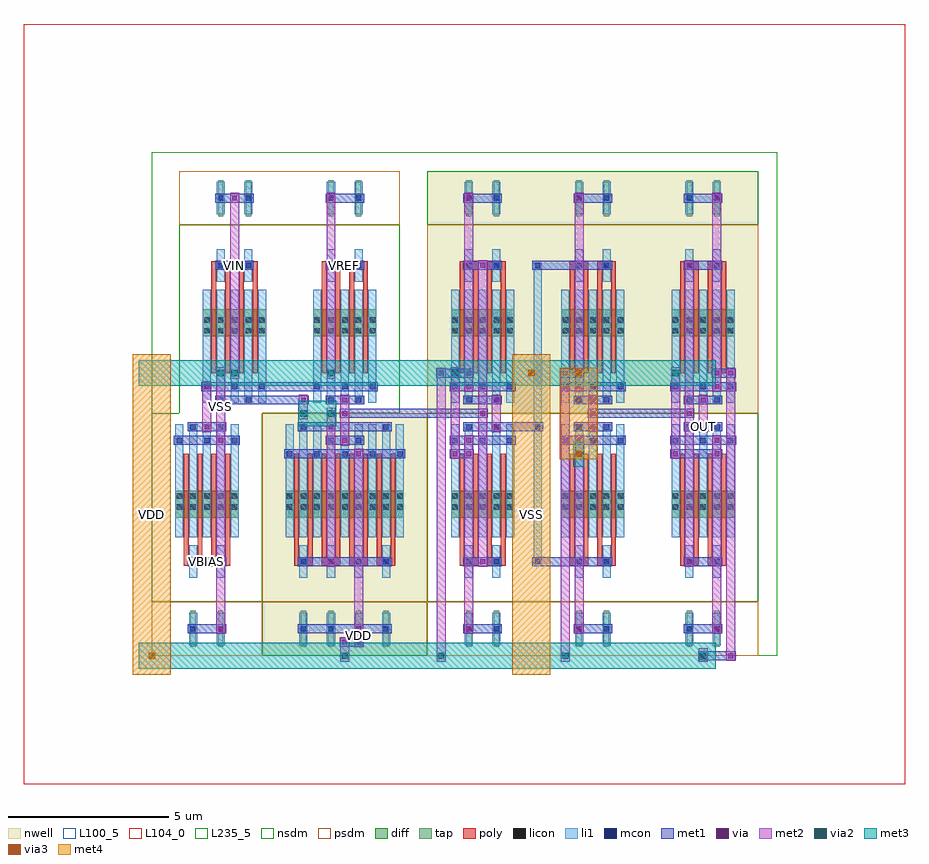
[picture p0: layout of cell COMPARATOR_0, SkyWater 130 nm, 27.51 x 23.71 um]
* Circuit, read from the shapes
.subckt COMPARATOR_0 OUT VBIAS VDD VIN VREF VSS
XM1 n1 VBIAS VSS VSS sky130_fd_pr__nfet_01v8 w=0.84 l=0.15 m=4
XM2 n2 VIN n1 VSS sky130_fd_pr__nfet_01v8 w=0.84 l=0.15 m=4
XM3 n3 VREF n1 VSS sky130_fd_pr__nfet_01v8 w=0.84 l=0.15 m=4
XM4 n4 n3 VSS VSS sky130_fd_pr__nfet_01v8 w=0.84 l=0.15 m=4
XM5 n5 n4 VSS VSS sky130_fd_pr__nfet_01v8 w=0.84 l=0.15 m=4
XM6 OUT n5 VSS VSS sky130_fd_pr__nfet_01v8 w=0.84 l=0.15 m=4
XM7 n2 n2 VDD VDD sky130_fd_pr__pfet_01v8 w=0.84 l=0.15 m=4
XM8 n3 n2 VDD VDD sky130_fd_pr__pfet_01v8 w=0.84 l=0.15 m=4
XM9 n4 n3 VDD VDD sky130_fd_pr__pfet_01v8 w=0.84 l=0.15 m=4
XM10 n5 n4 VDD VDD sky130_fd_pr__pfet_01v8 w=0.84 l=0.15 m=4
XM11 OUT n5 VDD VDD sky130_fd_pr__pfet_01v8 w=0.84 l=0.15 m=4
.ends

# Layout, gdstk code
from math import pi, radians
import gdstk
lib = gdstk.Library(unit=1e-6, precision=1e-09)
def R(c, l, rs):  # rectangles x0, y0, x1, y1
    for r in rs: c.add(gdstk.rectangle(r[:2], r[2:], *l))
def A(c, l, x, y, w, h, nx, ny, dx, dy):  # array of equal rectangles
    R(c, l, [(x+i*dx, y+j*dy, x+i*dx+w, y+j*dy+h) for i in range(nx) for j in range(ny)])
def P(c, l, *ps):  # polygons
    for p in ps: c.add(gdstk.Polygon(p, *l))
nwell = (64, 20)
diff = (65, 20)
tap = (65, 44)
poly = (66, 20)
licon = (66, 44)
li1 = (67, 20)
mcon = (67, 44)
met1 = (68, 20)
via = (68, 44)
met2 = (69, 20)
via2 = (69, 44)
met3 = (70, 20)
via3 = (70, 44)
met4 = (71, 20)
nsdm = (93, 44)
psdm = (94, 20)
L100_5 = (100, 5)
L104_0 = (104, 0)
L235_5 = (235, 5)

nmos_s_74334133_x2_y1_16 = lib.new_cell('NMOS_S_74334133_X2_Y1_1679758480_1679758482')
R(nmos_s_74334133_x2_y1_16, diff, [(0.735,2.415,2.705,3.255)])
R(nmos_s_74334133_x2_y1_16, tap, [(1.205,6.16,1.375,7.28), (2.065,6.16,2.235,7.28)])
A(nmos_s_74334133_x2_y1_16, poly, 1, 1.26, 0.15, 3.36, 4, 1, 0.43, 0)
R(nmos_s_74334133_x2_y1_16, poly, [(1,4.485,1.58,4.755), (1.86,4.485,2.44,4.755)])
A(nmos_s_74334133_x2_y1_16, licon, 0.775, 2.495, 0.17, 0.17, 3, 2, 0.43, 0.34)
A(nmos_s_74334133_x2_y1_16, licon, 1.635, 2.495, 0.17, 0.17, 3, 2, 0.43, 0.34)
R(nmos_s_74334133_x2_y1_16, licon, [(1.205,4.535,1.375,4.705), (2.065,4.535,2.235,4.705), (1.205,6.635,1.375,6.805), (2.065,6.635,2.235,6.805)])
A(nmos_s_74334133_x2_y1_16, li1, 0.735, 0.335, 0.25, 3.53, 5, 1, 0.43, 0)
R(nmos_s_74334133_x2_y1_16, li1, [(1.165,4.115,1.415,5.125), (2.025,4.115,2.275,5.125), (1.165,6.215,1.415,7.225), (2.025,6.215,2.275,7.225)])
A(nmos_s_74334133_x2_y1_16, mcon, 0.775, 0.755, 0.17, 0.17, 3, 1, 0.86, 0)
R(nmos_s_74334133_x2_y1_16, mcon, [(1.205,0.335,1.375,0.505), (2.065,0.335,2.235,0.505), (1.205,4.535,1.375,4.705), (2.065,4.535,2.235,4.705), (1.205,6.635,1.375,6.805), (2.065,6.635,2.235,6.805)])
R(nmos_s_74334133_x2_y1_16, met1, [(1.12,0.28,2.32,0.56), (0.69,0.7,2.75,0.98), (1.12,4.48,2.32,4.76), (1.12,6.58,2.32,6.86)])
R(nmos_s_74334133_x2_y1_16, via, [(2.075,0.765,2.225,0.915), (2.075,6.645,2.225,6.795)])
R(nmos_s_74334133_x2_y1_16, met2, [(2.01,0.68,2.29,6.88)])
R(nmos_s_74334133_x2_y1_16, nsdm, [(0,0,3.44,5.88)])
R(nmos_s_74334133_x2_y1_16, psdm, [(0,5.88,3.44,7.56)])
R(nmos_s_74334133_x2_y1_16, L100_5, [(0,0,3.44,7.56)])

pmos_s_33331942_x2_y1_16 = lib.new_cell('PMOS_S_33331942_X2_Y1_1679758481_1679758482')
R(pmos_s_33331942_x2_y1_16, nwell, [(0,0,3.44,7.56)])
R(pmos_s_33331942_x2_y1_16, diff, [(0.735,2.415,2.705,3.255)])
R(pmos_s_33331942_x2_y1_16, tap, [(1.205,6.16,1.375,7.28), (2.065,6.16,2.235,7.28)])
A(pmos_s_33331942_x2_y1_16, poly, 1, 1.26, 0.15, 3.36, 4, 1, 0.43, 0)
R(pmos_s_33331942_x2_y1_16, poly, [(1,4.485,1.58,4.755), (1.86,4.485,2.44,4.755)])
A(pmos_s_33331942_x2_y1_16, licon, 0.775, 2.495, 0.17, 0.17, 3, 2, 0.43, 0.34)
A(pmos_s_33331942_x2_y1_16, licon, 1.635, 2.495, 0.17, 0.17, 3, 2, 0.43, 0.34)
R(pmos_s_33331942_x2_y1_16, licon, [(1.205,4.535,1.375,4.705), (2.065,4.535,2.235,4.705), (1.205,6.635,1.375,6.805), (2.065,6.635,2.235,6.805)])
A(pmos_s_33331942_x2_y1_16, li1, 0.735, 0.335, 0.25, 3.53, 5, 1, 0.43, 0)
R(pmos_s_33331942_x2_y1_16, li1, [(1.165,4.115,1.415,5.125), (2.025,4.115,2.275,5.125), (1.165,6.215,1.415,7.225), (2.025,6.215,2.275,7.225)])
A(pmos_s_33331942_x2_y1_16, mcon, 0.775, 0.755, 0.17, 0.17, 3, 1, 0.86, 0)
R(pmos_s_33331942_x2_y1_16, mcon, [(1.205,0.335,1.375,0.505), (2.065,0.335,2.235,0.505), (1.205,4.535,1.375,4.705), (2.065,4.535,2.235,4.705), (1.205,6.635,1.375,6.805), (2.065,6.635,2.235,6.805)])
R(pmos_s_33331942_x2_y1_16, met1, [(1.12,0.28,2.32,0.56), (0.69,0.7,2.75,0.98), (1.12,4.48,2.32,4.76), (1.12,6.58,2.32,6.86)])
R(pmos_s_33331942_x2_y1_16, via, [(2.075,0.765,2.225,0.915), (2.075,6.645,2.225,6.795)])
R(pmos_s_33331942_x2_y1_16, met2, [(2.01,0.68,2.29,6.88)])
R(pmos_s_33331942_x2_y1_16, nsdm, [(0,5.88,3.44,7.56)])
R(pmos_s_33331942_x2_y1_16, psdm, [(0,0,3.44,5.88)])
R(pmos_s_33331942_x2_y1_16, L100_5, [(0,0,3.44,7.56)])

stage2_inv_90501218_pg0_ = lib.new_cell('STAGE2_INV_90501218_PG0_0_0_1679758482')
R(stage2_inv_90501218_pg0_, li1, [(3.315,2.855,3.565,3.025), (3.315,2.855,3.565,3.025), (3.315,2.855,3.565,3.025), (3.315,2.855,3.565,3.025), (3.315,2.855,3.565,3.025), (3.315,2.855,3.565,3.025), (3.315,2.94,3.565,7.14), (3.315,7.055,3.565,7.225), (3.315,7.055,3.565,7.225), (3.315,7.055,3.565,7.225), (3.315,7.055,3.565,7.225), (3.315,7.055,3.565,7.225), (3.315,7.055,3.565,7.225), (3.315,7.14,3.565,12.18), (3.315,12.095,3.565,12.265), (3.315,12.095,3.565,12.265)])
R(stage2_inv_90501218_pg0_, mcon, [(3.355,2.855,3.525,3.025), (3.355,2.855,3.525,3.025), (3.355,2.855,3.525,3.025), (3.355,2.855,3.525,3.025), (3.355,2.855,3.525,3.025), (3.355,2.855,3.525,3.025), (3.355,7.055,3.525,7.225), (3.355,7.055,3.525,7.225), (3.355,7.055,3.525,7.225), (3.355,7.055,3.525,7.225), (3.355,7.055,3.525,7.225), (3.355,7.055,3.525,7.225), (3.355,12.095,3.525,12.265), (3.355,12.095,3.525,12.265)])
R(stage2_inv_90501218_pg0_, met1, [(2.15,2.8,3.44,3.08), (3.27,2.8,3.61,3.08), (3.27,2.8,3.61,3.08), (3.27,2.8,3.61,3.08), (3.27,2.8,3.61,3.08), (3.27,2.8,3.61,3.08), (3.27,2.8,3.61,3.08), (5,2.8,5.32,3.08), (5,2.8,5.32,3.08), (1.56,7,1.88,7.28), (1.56,7,1.88,7.28), (3.27,7,3.61,7.28), (3.27,7,3.61,7.28), (3.27,7,3.61,7.28), (3.27,7,3.61,7.28), (3.27,7,3.61,7.28), (3.27,7,3.61,7.28), (3.44,7,4.73,7.28), (4.57,7,4.89,7.28), (4.57,7,4.89,7.28), (4.57,7,4.89,7.28), (4.57,7,4.89,7.28), (1.56,7.84,1.88,8.12), (1.56,7.84,1.88,8.12), (4.57,7.84,4.89,8.12), (4.57,7.84,4.89,8.12), (4.57,7.84,4.89,8.12), (4.57,7.84,4.89,8.12), (2.15,12.04,3.44,12.32), (3.27,12.04,3.61,12.32), (3.27,12.04,3.61,12.32), (5,12.04,5.32,12.32), (5,12.04,5.32,12.32)])
P(stage2_inv_90501218_pg0_, met1, [(0,0),(0,0),(0,0),(0,0)],
  [(0,0),(0,0),(0,0),(0,0)],
  [(0,0),(0,0),(0,0),(0,0)],
  [(0,0),(0,0),(0,0),(0,0)],
  [(0,0),(0,0),(0,0),(0,0)],
  [(0,0),(0,0),(0,0),(0,0)],
  [(0,0),(0,0),(0,0),(0,0)],
  [(0,0),(0,0),(0,0),(0,0)])
R(stage2_inv_90501218_pg0_, via, [(5.085,2.865,5.235,3.015), (5.085,2.865,5.235,3.015), (1.645,7.065,1.795,7.215), (1.645,7.065,1.795,7.215), (4.655,7.065,4.805,7.215), (4.655,7.065,4.805,7.215), (4.655,7.065,4.805,7.215), (4.655,7.065,4.805,7.215), (1.645,7.905,1.795,8.055), (1.645,7.905,1.795,8.055), (4.655,7.905,4.805,8.055), (4.655,7.905,4.805,8.055), (4.655,7.905,4.805,8.055), (4.655,7.905,4.805,8.055), (5.085,12.105,5.235,12.255), (5.085,12.105,5.235,12.255)])
R(stage2_inv_90501218_pg0_, met2, [(5.02,2.78,5.3,3.1), (5.02,2.78,5.3,3.1), (5.02,2.94,5.3,12.18), (1.58,6.98,1.86,7.3), (1.58,6.98,1.86,7.3), (4.59,6.98,4.87,7.3), (4.59,6.98,4.87,7.3), (4.59,6.98,4.87,7.3), (4.59,6.98,4.87,7.3), (1.58,7.14,1.86,7.98), (4.59,7.14,4.87,7.98), (1.58,7.82,1.86,8.14), (1.58,7.82,1.86,8.14), (4.59,7.82,4.87,8.14), (4.59,7.82,4.87,8.14), (4.59,7.82,4.87,8.14), (4.59,7.82,4.87,8.14), (5.02,12.02,5.3,12.34), (5.02,12.02,5.3,12.34)])
P(stage2_inv_90501218_pg0_, met2, [(0,0),(0,0),(0,0),(0,0)],
  [(0,0),(0,0),(0,0),(0,0)],
  [(0,0),(0,0),(0,0),(0,0)],
  [(0,0),(0,0),(0,0),(0,0)])
R(stage2_inv_90501218_pg0_, L235_5, [(0,0,6.88,15.12)])
stage2_inv_90501218_pg0_.add(gdstk.Reference(nmos_s_74334133_x2_y1_16, (3.44,7.56), x_reflection=True))
stage2_inv_90501218_pg0_.add(gdstk.Reference(nmos_s_74334133_x2_y1_16, (0,7.56), x_reflection=True))
stage2_inv_90501218_pg0_.add(gdstk.Reference(pmos_s_33331942_x2_y1_16, (3.44,7.56)))
stage2_inv_90501218_pg0_.add(gdstk.Reference(pmos_s_33331942_x2_y1_16, (0,7.56)))

scm_pmos_23436893_x2_y1_ = lib.new_cell('SCM_PMOS_23436893_X2_Y1_1679758485')
R(scm_pmos_23436893_x2_y1_, nwell, [(0,0,5.16,7.56)])
R(scm_pmos_23436893_x2_y1_, diff, [(0.735,2.415,4.425,3.255)])
A(scm_pmos_23436893_x2_y1_, tap, 1.205, 6.16, 0.17, 1.12, 4, 1, 0.86, 0)
A(scm_pmos_23436893_x2_y1_, poly, 1, 1.26, 0.15, 3.36, 8, 1, 0.43, 0)
A(scm_pmos_23436893_x2_y1_, poly, 1, 4.485, 0.58, 0.27, 4, 1, 0.86, 0)
A(scm_pmos_23436893_x2_y1_, licon, 0.775, 2.495, 0.17, 0.17, 3, 2, 0.43, 0.34)
A(scm_pmos_23436893_x2_y1_, licon, 1.635, 2.495, 0.17, 0.17, 3, 2, 0.43, 0.34)
A(scm_pmos_23436893_x2_y1_, licon, 2.495, 2.495, 0.17, 0.17, 3, 2, 0.43, 0.34)
A(scm_pmos_23436893_x2_y1_, licon, 3.355, 2.495, 0.17, 0.17, 3, 2, 0.43, 0.34)
A(scm_pmos_23436893_x2_y1_, licon, 1.205, 4.535, 0.17, 0.17, 4, 2, 0.86, 2.1)
A(scm_pmos_23436893_x2_y1_, li1, 0.735, 0.335, 0.25, 3.53, 9, 1, 0.43, 0)
A(scm_pmos_23436893_x2_y1_, li1, 1.165, 4.115, 0.25, 1.01, 4, 2, 0.86, 2.1)
A(scm_pmos_23436893_x2_y1_, mcon, 0.775, 1.175, 0.17, 0.17, 5, 1, 0.86, 0)
A(scm_pmos_23436893_x2_y1_, mcon, 1.205, 4.535, 0.17, 0.17, 4, 2, 0.86, 2.1)
R(scm_pmos_23436893_x2_y1_, mcon, [(1.205,0.335,1.375,0.505), (3.785,0.335,3.955,0.505), (2.065,0.755,2.235,0.925), (2.925,0.755,3.095,0.925)])
R(scm_pmos_23436893_x2_y1_, met1, [(1.12,0.28,4.04,0.56), (1.98,0.7,3.18,0.98), (0.69,1.12,4.47,1.4), (1.12,4.48,4.04,4.76), (1.12,6.58,4.04,6.86)])
R(scm_pmos_23436893_x2_y1_, via, [(2.075,0.345,2.225,0.495), (2.935,1.185,3.085,1.335), (2.075,4.545,2.225,4.695), (2.935,6.645,3.085,6.795)])
R(scm_pmos_23436893_x2_y1_, met2, [(2.01,0.26,2.29,4.78), (2.87,1.1,3.15,6.88)])
R(scm_pmos_23436893_x2_y1_, nsdm, [(0,5.88,5.16,7.56)])
R(scm_pmos_23436893_x2_y1_, psdm, [(0,0,5.16,5.88)])
R(scm_pmos_23436893_x2_y1_, L100_5, [(0,0,5.16,7.56)])

c_nmos_s_74334133_x2_y1_16 = lib.new_cell('NMOS_S_74334133_X2_Y1_1679758480_1679758481')
R(c_nmos_s_74334133_x2_y1_16, diff, [(0.735,2.415,2.705,3.255)])
R(c_nmos_s_74334133_x2_y1_16, tap, [(1.205,6.16,1.375,7.28), (2.065,6.16,2.235,7.28)])
A(c_nmos_s_74334133_x2_y1_16, poly, 1, 1.26, 0.15, 3.36, 4, 1, 0.43, 0)
R(c_nmos_s_74334133_x2_y1_16, poly, [(1,4.485,1.58,4.755), (1.86,4.485,2.44,4.755)])
A(c_nmos_s_74334133_x2_y1_16, licon, 0.775, 2.495, 0.17, 0.17, 3, 2, 0.43, 0.34)
A(c_nmos_s_74334133_x2_y1_16, licon, 1.635, 2.495, 0.17, 0.17, 3, 2, 0.43, 0.34)
R(c_nmos_s_74334133_x2_y1_16, licon, [(1.205,4.535,1.375,4.705), (2.065,4.535,2.235,4.705), (1.205,6.635,1.375,6.805), (2.065,6.635,2.235,6.805)])
A(c_nmos_s_74334133_x2_y1_16, li1, 0.735, 0.335, 0.25, 3.53, 5, 1, 0.43, 0)
R(c_nmos_s_74334133_x2_y1_16, li1, [(1.165,4.115,1.415,5.125), (2.025,4.115,2.275,5.125), (1.165,6.215,1.415,7.225), (2.025,6.215,2.275,7.225)])
A(c_nmos_s_74334133_x2_y1_16, mcon, 0.775, 0.755, 0.17, 0.17, 3, 1, 0.86, 0)
R(c_nmos_s_74334133_x2_y1_16, mcon, [(1.205,0.335,1.375,0.505), (2.065,0.335,2.235,0.505), (1.205,4.535,1.375,4.705), (2.065,4.535,2.235,4.705), (1.205,6.635,1.375,6.805), (2.065,6.635,2.235,6.805)])
R(c_nmos_s_74334133_x2_y1_16, met1, [(1.12,0.28,2.32,0.56), (0.69,0.7,2.75,0.98), (1.12,4.48,2.32,4.76), (1.12,6.58,2.32,6.86)])
R(c_nmos_s_74334133_x2_y1_16, via, [(2.075,0.765,2.225,0.915), (2.075,6.645,2.225,6.795)])
R(c_nmos_s_74334133_x2_y1_16, met2, [(2.01,0.68,2.29,6.88)])
R(c_nmos_s_74334133_x2_y1_16, nsdm, [(0,0,3.44,5.88)])
R(c_nmos_s_74334133_x2_y1_16, psdm, [(0,5.88,3.44,7.56)])
R(c_nmos_s_74334133_x2_y1_16, L100_5, [(0,0,3.44,7.56)])

c_pmos_s_33331942_x2_y1_16 = lib.new_cell('PMOS_S_33331942_X2_Y1_1679758481_1679758481')
R(c_pmos_s_33331942_x2_y1_16, nwell, [(0,0,3.44,7.56)])
R(c_pmos_s_33331942_x2_y1_16, diff, [(0.735,2.415,2.705,3.255)])
R(c_pmos_s_33331942_x2_y1_16, tap, [(1.205,6.16,1.375,7.28), (2.065,6.16,2.235,7.28)])
A(c_pmos_s_33331942_x2_y1_16, poly, 1, 1.26, 0.15, 3.36, 4, 1, 0.43, 0)
R(c_pmos_s_33331942_x2_y1_16, poly, [(1,4.485,1.58,4.755), (1.86,4.485,2.44,4.755)])
A(c_pmos_s_33331942_x2_y1_16, licon, 0.775, 2.495, 0.17, 0.17, 3, 2, 0.43, 0.34)
A(c_pmos_s_33331942_x2_y1_16, licon, 1.635, 2.495, 0.17, 0.17, 3, 2, 0.43, 0.34)
R(c_pmos_s_33331942_x2_y1_16, licon, [(1.205,4.535,1.375,4.705), (2.065,4.535,2.235,4.705), (1.205,6.635,1.375,6.805), (2.065,6.635,2.235,6.805)])
A(c_pmos_s_33331942_x2_y1_16, li1, 0.735, 0.335, 0.25, 3.53, 5, 1, 0.43, 0)
R(c_pmos_s_33331942_x2_y1_16, li1, [(1.165,4.115,1.415,5.125), (2.025,4.115,2.275,5.125), (1.165,6.215,1.415,7.225), (2.025,6.215,2.275,7.225)])
A(c_pmos_s_33331942_x2_y1_16, mcon, 0.775, 0.755, 0.17, 0.17, 3, 1, 0.86, 0)
R(c_pmos_s_33331942_x2_y1_16, mcon, [(1.205,0.335,1.375,0.505), (2.065,0.335,2.235,0.505), (1.205,4.535,1.375,4.705), (2.065,4.535,2.235,4.705), (1.205,6.635,1.375,6.805), (2.065,6.635,2.235,6.805)])
R(c_pmos_s_33331942_x2_y1_16, met1, [(1.12,0.28,2.32,0.56), (0.69,0.7,2.75,0.98), (1.12,4.48,2.32,4.76), (1.12,6.58,2.32,6.86)])
R(c_pmos_s_33331942_x2_y1_16, via, [(2.075,0.765,2.225,0.915), (2.075,6.645,2.225,6.795)])
R(c_pmos_s_33331942_x2_y1_16, met2, [(2.01,0.68,2.29,6.88)])
R(c_pmos_s_33331942_x2_y1_16, nsdm, [(0,5.88,3.44,7.56)])
R(c_pmos_s_33331942_x2_y1_16, psdm, [(0,0,3.44,5.88)])
R(c_pmos_s_33331942_x2_y1_16, L100_5, [(0,0,3.44,7.56)])

inv_46031338_pg0_0_0_167 = lib.new_cell('INV_46031338_PG0_0_0_1679758481')
R(inv_46031338_pg0_0_0_167, met1, [(1.13,2.8,1.45,3.08), (1.13,2.8,1.45,3.08), (1.56,7,1.88,7.28), (1.56,7,1.88,7.28), (1.56,7.84,1.88,8.12), (1.56,7.84,1.88,8.12), (1.13,12.04,1.45,12.32), (1.13,12.04,1.45,12.32)])
P(inv_46031338_pg0_0_0_167, met1, [(0,0),(0,0),(0,0),(0,0)],
  [(0,0),(0,0),(0,0),(0,0)],
  [(0,0),(0,0),(0,0),(0,0)],
  [(0,0),(0,0),(0,0),(0,0)])
R(inv_46031338_pg0_0_0_167, via, [(1.215,2.865,1.365,3.015), (1.215,2.865,1.365,3.015), (1.645,7.065,1.795,7.215), (1.645,7.065,1.795,7.215), (1.645,7.905,1.795,8.055), (1.645,7.905,1.795,8.055), (1.215,12.105,1.365,12.255), (1.215,12.105,1.365,12.255)])
R(inv_46031338_pg0_0_0_167, met2, [(1.15,2.78,1.43,3.1), (1.15,2.78,1.43,3.1), (1.15,2.94,1.43,12.18), (1.58,6.98,1.86,7.3), (1.58,6.98,1.86,7.3), (1.58,7.14,1.86,7.98), (1.58,7.82,1.86,8.14), (1.58,7.82,1.86,8.14), (1.15,12.02,1.43,12.34), (1.15,12.02,1.43,12.34)])
P(inv_46031338_pg0_0_0_167, met2, [(0,0),(0,0),(0,0),(0,0)],
  [(0,0),(0,0),(0,0),(0,0)])
R(inv_46031338_pg0_0_0_167, L235_5, [(0,0,3.44,15.12)])
inv_46031338_pg0_0_0_167.add(gdstk.Reference(c_nmos_s_74334133_x2_y1_16, (0,7.56), x_reflection=True))
inv_46031338_pg0_0_0_167.add(gdstk.Reference(c_pmos_s_33331942_x2_y1_16, (0,7.56)))

c_nmos_s_74334133_x2_y1_16_ = lib.new_cell('NMOS_S_74334133_X2_Y1_1679758484')
R(c_nmos_s_74334133_x2_y1_16_, diff, [(0.735,2.415,2.705,3.255)])
R(c_nmos_s_74334133_x2_y1_16_, tap, [(1.205,6.16,1.375,7.28), (2.065,6.16,2.235,7.28)])
A(c_nmos_s_74334133_x2_y1_16_, poly, 1, 1.26, 0.15, 3.36, 4, 1, 0.43, 0)
R(c_nmos_s_74334133_x2_y1_16_, poly, [(1,4.485,1.58,4.755), (1.86,4.485,2.44,4.755)])
A(c_nmos_s_74334133_x2_y1_16_, licon, 0.775, 2.495, 0.17, 0.17, 3, 2, 0.43, 0.34)
A(c_nmos_s_74334133_x2_y1_16_, licon, 1.635, 2.495, 0.17, 0.17, 3, 2, 0.43, 0.34)
R(c_nmos_s_74334133_x2_y1_16_, licon, [(1.205,4.535,1.375,4.705), (2.065,4.535,2.235,4.705), (1.205,6.635,1.375,6.805), (2.065,6.635,2.235,6.805)])
A(c_nmos_s_74334133_x2_y1_16_, li1, 0.735, 0.335, 0.25, 3.53, 5, 1, 0.43, 0)
R(c_nmos_s_74334133_x2_y1_16_, li1, [(1.165,4.115,1.415,5.125), (2.025,4.115,2.275,5.125), (1.165,6.215,1.415,7.225), (2.025,6.215,2.275,7.225)])
A(c_nmos_s_74334133_x2_y1_16_, mcon, 0.775, 0.755, 0.17, 0.17, 3, 1, 0.86, 0)
R(c_nmos_s_74334133_x2_y1_16_, mcon, [(1.205,0.335,1.375,0.505), (2.065,0.335,2.235,0.505), (1.205,4.535,1.375,4.705), (2.065,4.535,2.235,4.705), (1.205,6.635,1.375,6.805), (2.065,6.635,2.235,6.805)])
R(c_nmos_s_74334133_x2_y1_16_, met1, [(1.12,0.28,2.32,0.56), (0.69,0.7,2.75,0.98), (1.12,4.48,2.32,4.76), (1.12,6.58,2.32,6.86)])
R(c_nmos_s_74334133_x2_y1_16_, via, [(2.075,0.765,2.225,0.915), (2.075,6.645,2.225,6.795)])
R(c_nmos_s_74334133_x2_y1_16_, met2, [(2.01,0.68,2.29,6.88)])
R(c_nmos_s_74334133_x2_y1_16_, nsdm, [(0,0,3.44,5.88)])
R(c_nmos_s_74334133_x2_y1_16_, psdm, [(0,5.88,3.44,7.56)])
R(c_nmos_s_74334133_x2_y1_16_, L100_5, [(0,0,3.44,7.56)])

nmos_4t_77406006_x2_y1_1 = lib.new_cell('NMOS_4T_77406006_X2_Y1_1679758483')
R(nmos_4t_77406006_x2_y1_1, diff, [(0.735,2.415,2.705,3.255)])
R(nmos_4t_77406006_x2_y1_1, tap, [(1.205,6.16,1.375,7.28), (2.065,6.16,2.235,7.28)])
A(nmos_4t_77406006_x2_y1_1, poly, 1, 1.26, 0.15, 3.36, 4, 1, 0.43, 0)
R(nmos_4t_77406006_x2_y1_1, poly, [(1,4.485,1.58,4.755), (1.86,4.485,2.44,4.755)])
A(nmos_4t_77406006_x2_y1_1, licon, 0.775, 2.495, 0.17, 0.17, 3, 2, 0.43, 0.34)
A(nmos_4t_77406006_x2_y1_1, licon, 1.635, 2.495, 0.17, 0.17, 3, 2, 0.43, 0.34)
R(nmos_4t_77406006_x2_y1_1, licon, [(1.205,4.535,1.375,4.705), (2.065,4.535,2.235,4.705), (1.205,6.635,1.375,6.805), (2.065,6.635,2.235,6.805)])
A(nmos_4t_77406006_x2_y1_1, li1, 0.735, 0.335, 0.25, 3.53, 5, 1, 0.43, 0)
R(nmos_4t_77406006_x2_y1_1, li1, [(1.165,4.115,1.415,5.125), (2.025,4.115,2.275,5.125), (1.165,6.215,1.415,7.225), (2.025,6.215,2.275,7.225)])
A(nmos_4t_77406006_x2_y1_1, mcon, 0.775, 0.755, 0.17, 0.17, 3, 1, 0.86, 0)
R(nmos_4t_77406006_x2_y1_1, mcon, [(1.205,0.335,1.375,0.505), (2.065,0.335,2.235,0.505), (1.205,4.535,1.375,4.705), (2.065,4.535,2.235,4.705), (1.205,6.635,1.375,6.805), (2.065,6.635,2.235,6.805)])
R(nmos_4t_77406006_x2_y1_1, met1, [(1.12,0.28,2.32,0.56), (0.69,0.7,2.75,0.98), (1.12,4.48,2.32,4.76), (1.12,6.58,2.32,6.86)])
R(nmos_4t_77406006_x2_y1_1, nsdm, [(0,0,3.44,5.88)])
R(nmos_4t_77406006_x2_y1_1, psdm, [(0,5.88,3.44,7.56)])
R(nmos_4t_77406006_x2_y1_1, L100_5, [(0,0,3.44,7.56)])

comparator_0 = lib.new_cell('COMPARATOR_0')
R(comparator_0, met1, [(17.04,-0.14,17.36,0.14), (17.04,-0.14,17.36,0.14), (17.2,-0.14,18.06,0.14), (17.9,-0.14,18.22,0.14), (17.9,-0.14,18.22,0.14), (5.86,0.28,6.18,0.56), (5.86,0.28,6.18,0.56), (5.86,0.28,6.18,0.56), (5.86,0.28,6.18,0.56), (5.86,0.28,6.18,0.56), (6.02,0.28,6.45,0.56), (6.29,0.28,6.61,0.56), (6.29,0.28,6.61,0.56), (6.29,0.28,6.61,0.56), (6.29,0.28,6.61,0.56), (6.29,0.28,6.61,0.56), (9.3,6.16,9.62,6.44), (9.3,6.16,9.62,6.44), (9.3,6.16,9.62,6.44), (9.3,6.16,9.62,6.44), (9.46,6.16,9.89,6.44), (9.73,6.16,10.05,6.44), (9.73,6.16,10.05,6.44), (9.73,6.16,10.05,6.44), (9.73,6.16,10.05,6.44), (16.18,6.16,16.5,6.44), (16.18,6.16,16.5,6.44), (16.34,6.16,17.63,6.44), (17.47,6.16,17.79,6.44), (17.47,6.16,17.79,6.44), (5.86,6.58,6.18,6.86), (5.86,6.58,6.18,6.86), (5.86,6.58,6.18,6.86), (5.86,6.58,6.18,6.86), (1.56,7,1.88,7.28), (1.56,7,1.88,7.28), (1.56,7,1.88,7.28), (1.56,7,1.88,7.28), (5.86,7.42,6.18,7.7), (5.86,7.42,6.18,7.7), (6.02,7.42,10.32,7.7), (10.16,7.42,10.48,7.7), (10.16,7.42,10.48,7.7), (13.6,7.42,13.92,7.7), (13.6,7.42,13.92,7.7), (13.76,7.42,16.77,7.7), (16.61,7.42,16.93,7.7), (16.61,7.42,16.93,7.7), (3.01,7.84,4.73,8.12), (4.57,7.84,4.89,8.12), (4.57,7.84,4.89,8.12), (5.86,7.84,6.18,8.12), (5.86,7.84,6.18,8.12), (5.86,7.84,6.18,8.12), (5.86,7.84,6.18,8.12), (1.56,8.26,1.88,8.54), (1.56,8.26,1.88,8.54), (1.56,8.26,1.88,8.54), (1.56,8.26,1.88,8.54), (3.44,8.26,5.16,8.54), (8.87,8.68,9.19,8.96), (8.87,8.68,9.19,8.96), (8.87,8.68,9.19,8.96), (8.87,8.68,9.19,8.96), (9.03,8.68,9.89,8.96), (9.73,8.68,10.05,8.96), (9.73,8.68,10.05,8.96), (9.73,8.68,10.05,8.96), (9.73,8.68,10.05,8.96), (12.74,8.68,13.06,8.96), (12.74,8.68,13.06,8.96), (12.74,8.68,13.06,8.96), (12.9,8.68,13.33,8.96), (13.17,8.68,13.49,8.96), (13.17,8.68,13.49,8.96), (13.17,8.68,13.49,8.96), (17.47,8.68,17.79,8.96), (17.47,8.68,17.79,8.96), (17.63,8.68,18.06,8.96), (17.9,8.68,18.22,8.96), (17.9,8.68,18.22,8.96), (2.42,14.14,2.74,14.42), (2.42,14.14,2.74,14.42), (2.42,14.14,2.74,14.42), (2.42,14.14,2.74,14.42), (2.42,14.14,2.74,14.42), (2.42,14.14,2.74,14.42), (5.43,14.14,5.75,14.42), (5.43,14.14,5.75,14.42), (5.43,14.14,5.75,14.42), (5.43,14.14,5.75,14.42), (5.43,14.14,5.75,14.42)])
P(comparator_0, met1, [(0,0),(0,0),(0,0),(0,0)],
  [(0,0),(0,0),(0,0),(0,0)],
  [(0,0),(0,0),(0,0),(0,0)],
  [(0,0),(0,0),(0,0),(0,0)],
  [(0,0),(0,0),(0,0),(0,0)],
  [(0,0),(0,0),(0,0),(0,0)],
  [(0,0),(0,0),(0,0),(0,0)],
  [(0,0),(0,0),(0,0),(0,0)],
  [(0,0),(0,0),(0,0),(0,0)],
  [(0,0),(0,0),(0,0),(0,0)],
  [(0,0),(0,0),(0,0),(0,0)],
  [(0,0),(0,0),(0,0),(0,0)],
  [(0,0),(0,0),(0,0),(0,0)],
  [(0,0),(0,0),(0,0),(0,0)],
  [(0,0),(0,0),(0,0),(0,0)],
  [(0,0),(0,0),(0,0),(0,0)],
  [(0,0),(0,0),(0,0),(0,0)],
  [(0,0),(0,0),(0,0),(0,0)],
  [(0,0),(0,0),(0,0),(0,0)],
  [(0,0),(0,0),(0,0),(0,0)],
  [(0,0),(0,0),(0,0),(0,0)],
  [(0,0),(0,0),(0,0),(0,0)],
  [(0,0),(0,0),(0,0),(0,0)],
  [(0,0),(0,0),(0,0),(0,0)],
  [(0,0),(0,0),(0,0),(0,0)],
  [(0,0),(0,0),(0,0),(0,0)],
  [(0,0),(0,0),(0,0),(0,0)],
  [(0,0),(0,0),(0,0),(0,0)],
  [(0,0),(0,0),(0,0),(0,0)],
  [(0,0),(0,0),(0,0),(0,0)],
  [(0,0),(0,0),(0,0),(0,0)])
R(comparator_0, via, [(17.125,-0.075,17.275,0.075), (17.125,-0.075,17.275,0.075), (17.985,-0.075,18.135,0.075), (17.985,-0.075,18.135,0.075), (5.945,0.345,6.095,0.495), (5.945,0.345,6.095,0.495), (5.945,0.345,6.095,0.495), (5.945,0.345,6.095,0.495), (5.945,0.345,6.095,0.495), (6.375,0.345,6.525,0.495), (6.375,0.345,6.525,0.495), (6.375,0.345,6.525,0.495), (6.375,0.345,6.525,0.495), (6.375,0.345,6.525,0.495), (9.385,6.225,9.535,6.375), (9.385,6.225,9.535,6.375), (9.385,6.225,9.535,6.375), (9.385,6.225,9.535,6.375), (9.815,6.225,9.965,6.375), (9.815,6.225,9.965,6.375), (9.815,6.225,9.965,6.375), (9.815,6.225,9.965,6.375), (16.265,6.225,16.415,6.375), (16.265,6.225,16.415,6.375), (17.555,6.225,17.705,6.375), (17.555,6.225,17.705,6.375), (5.945,6.645,6.095,6.795), (5.945,6.645,6.095,6.795), (5.945,6.645,6.095,6.795), (5.945,6.645,6.095,6.795), (1.645,7.065,1.795,7.215), (1.645,7.065,1.795,7.215), (1.645,7.065,1.795,7.215), (1.645,7.065,1.795,7.215), (5.945,7.485,6.095,7.635), (5.945,7.485,6.095,7.635), (10.245,7.485,10.395,7.635), (10.245,7.485,10.395,7.635), (13.685,7.485,13.835,7.635), (13.685,7.485,13.835,7.635), (16.695,7.485,16.845,7.635), (16.695,7.485,16.845,7.635), (4.655,7.905,4.805,8.055), (4.655,7.905,4.805,8.055), (5.945,7.905,6.095,8.055), (5.945,7.905,6.095,8.055), (5.945,7.905,6.095,8.055), (5.945,7.905,6.095,8.055), (1.645,8.325,1.795,8.475), (1.645,8.325,1.795,8.475), (1.645,8.325,1.795,8.475), (1.645,8.325,1.795,8.475), (8.955,8.745,9.105,8.895), (8.955,8.745,9.105,8.895), (8.955,8.745,9.105,8.895), (8.955,8.745,9.105,8.895), (9.815,8.745,9.965,8.895), (9.815,8.745,9.965,8.895), (9.815,8.745,9.965,8.895), (9.815,8.745,9.965,8.895), (12.825,8.745,12.975,8.895), (12.825,8.745,12.975,8.895), (12.825,8.745,12.975,8.895), (13.255,8.745,13.405,8.895), (13.255,8.745,13.405,8.895), (13.255,8.745,13.405,8.895), (17.555,8.745,17.705,8.895), (17.555,8.745,17.705,8.895), (17.985,8.745,18.135,8.895), (17.985,8.745,18.135,8.895), (2.505,14.205,2.655,14.355), (2.505,14.205,2.655,14.355), (2.505,14.205,2.655,14.355), (2.505,14.205,2.655,14.355), (2.505,14.205,2.655,14.355), (2.505,14.205,2.655,14.355), (5.515,14.205,5.665,14.355), (5.515,14.205,5.665,14.355), (5.515,14.205,5.665,14.355), (5.515,14.205,5.665,14.355), (5.515,14.205,5.665,14.355)])
R(comparator_0, met2, [(5.88,-0.185,6.16,0.185), (5.88,-0.185,6.16,0.185), (5.88,-0.185,6.16,0.185), (5.88,-0.185,6.16,0.185), (5.88,-0.185,6.16,0.185), (8.89,-0.185,9.17,0.185), (8.89,-0.185,9.17,0.185), (8.89,-0.185,9.17,0.185), (8.89,-0.185,9.17,0.185), (12.76,-0.185,13.04,0.185), (12.76,-0.185,13.04,0.185), (12.76,-0.185,13.04,0.185), (17.06,-0.185,17.34,0.185), (17.06,-0.185,17.34,0.185), (17.06,-0.16,17.34,0.16), (17.06,-0.16,17.34,0.16), (17.92,-0.16,18.2,0.16), (17.92,-0.16,18.2,0.16), (5.88,0,6.16,0.42), (8.89,0,9.17,8.82), (12.76,0,13.04,8.82), (17.06,0,17.34,0.242), (17.92,0,18.2,8.82), (5.88,0.26,6.16,0.58), (5.88,0.26,6.16,0.58), (5.88,0.26,6.16,0.58), (5.88,0.26,6.16,0.58), (5.88,0.26,6.16,0.58), (6.31,0.26,6.59,0.58), (6.31,0.26,6.59,0.58), (6.31,0.26,6.59,0.58), (6.31,0.26,6.59,0.58), (6.31,0.26,6.59,0.58), (6.31,0.42,6.59,0.84), (13.19,6.115,13.47,6.485), (9.32,6.14,9.6,6.46), (9.32,6.14,9.6,6.46), (9.32,6.14,9.6,6.46), (9.32,6.14,9.6,6.46), (9.75,6.14,10.03,6.46), (9.75,6.14,10.03,6.46), (9.75,6.14,10.03,6.46), (9.75,6.14,10.03,6.46), (16.2,6.14,16.48,6.46), (16.2,6.14,16.48,6.46), (17.49,6.14,17.77,6.46), (17.49,6.14,17.77,6.46), (9.32,6.3,9.6,8.82), (16.2,6.3,16.48,8.82), (5.88,6.56,6.16,6.88), (5.88,6.56,6.16,6.88), (5.88,6.56,6.16,6.88), (5.88,6.56,6.16,6.88), (2.01,6.72,2.29,8.82), (5.88,6.72,6.16,7.98), (1.58,6.98,1.86,7.3), (1.58,6.98,1.86,7.3), (1.58,6.98,1.86,7.3), (1.58,6.98,1.86,7.3), (1.58,7.14,1.86,8.4), (5.45,7.14,5.73,7.56), (4.59,7.375,4.87,7.745), (4.59,7.375,4.87,7.745), (5.45,7.375,5.73,7.745), (5.45,7.375,5.73,7.745), (5.88,7.4,6.16,7.72), (5.88,7.4,6.16,7.72), (10.18,7.4,10.46,7.72), (10.18,7.4,10.46,7.72), (13.62,7.4,13.9,7.72), (13.62,7.4,13.9,7.72), (16.63,7.4,16.91,7.72), (16.63,7.4,16.91,7.72), (4.59,7.56,4.87,7.98), (4.59,7.82,4.87,8.14), (4.59,7.82,4.87,8.14), (5.88,7.82,6.16,8.14), (5.88,7.82,6.16,8.14), (5.88,7.82,6.16,8.14), (5.88,7.82,6.16,8.14), (1.58,8.24,1.86,8.56), (1.58,8.24,1.86,8.56), (1.58,8.24,1.86,8.56), (1.58,8.24,1.86,8.56), (2.01,8.635,2.29,9.005), (2.01,8.635,2.29,9.005), (2.01,8.635,2.29,9.005), (2.01,8.635,2.29,9.005), (2.01,8.635,2.29,9.005), (2.01,8.635,2.29,9.005), (2.01,8.635,2.29,9.005), (2.44,8.635,2.72,9.005), (2.44,8.635,2.72,9.005), (2.44,8.635,2.72,9.005), (2.44,8.635,2.72,9.005), (2.44,8.635,2.72,9.005), (2.44,8.635,2.72,9.005), (5.45,8.635,5.73,9.005), (5.45,8.635,5.73,9.005), (5.45,8.635,5.73,9.005), (5.45,8.635,5.73,9.005), (5.45,8.635,5.73,9.005), (9.32,8.635,9.6,9.005), (9.32,8.635,9.6,9.005), (9.32,8.635,9.6,9.005), (9.32,8.635,9.6,9.005), (16.2,8.635,16.48,9.005), (16.2,8.635,16.48,9.005), (8.89,8.66,9.17,8.98), (8.89,8.66,9.17,8.98), (8.89,8.66,9.17,8.98), (8.89,8.66,9.17,8.98), (9.75,8.66,10.03,8.98), (9.75,8.66,10.03,8.98), (9.75,8.66,10.03,8.98), (9.75,8.66,10.03,8.98), (12.76,8.66,13.04,8.98), (12.76,8.66,13.04,8.98), (12.76,8.66,13.04,8.98), (13.19,8.66,13.47,8.98), (13.19,8.66,13.47,8.98), (13.19,8.66,13.47,8.98), (17.49,8.66,17.77,8.98), (17.49,8.66,17.77,8.98), (17.92,8.66,18.2,8.98), (17.92,8.66,18.2,8.98), (2.44,8.82,2.72,14.28), (5.45,8.82,5.73,14.28), (2.44,14.12,2.72,14.44), (2.44,14.12,2.72,14.44), (2.44,14.12,2.72,14.44), (2.44,14.12,2.72,14.44), (2.44,14.12,2.72,14.44), (2.44,14.12,2.72,14.44), (5.45,14.12,5.73,14.44), (5.45,14.12,5.73,14.44), (5.45,14.12,5.73,14.44), (5.45,14.12,5.73,14.44), (5.45,14.12,5.73,14.44)])
P(comparator_0, met2, [(0,0),(0,0),(0,0),(0,0)],
  [(0,0),(0,0),(0,0),(0,0)],
  [(0,0),(0,0),(0,0),(0,0)],
  [(0,0),(0,0),(0,0),(0,0)],
  [(0,0),(0,0),(0,0),(0,0)],
  [(0,0),(0,0),(0,0),(0,0)],
  [(0,0),(0,0),(0,0),(0,0)])
R(comparator_0, via2, [(5.92,-0.1,6.12,0.1), (5.92,-0.1,6.12,0.1), (5.92,-0.1,6.12,0.1), (5.92,-0.1,6.12,0.1), (5.92,-0.1,6.12,0.1), (8.93,-0.1,9.13,0.1), (8.93,-0.1,9.13,0.1), (8.93,-0.1,9.13,0.1), (8.93,-0.1,9.13,0.1), (12.8,-0.1,13,0.1), (12.8,-0.1,13,0.1), (12.8,-0.1,13,0.1), (17.1,-0.1,17.3,0.1), (17.1,-0.1,17.3,0.1), (13.23,6.2,13.43,6.4), (4.63,7.46,4.83,7.66), (4.63,7.46,4.83,7.66), (5.49,7.46,5.69,7.66), (5.49,7.46,5.69,7.66), (2.05,8.72,2.25,8.92), (2.05,8.72,2.25,8.92), (2.05,8.72,2.25,8.92), (2.05,8.72,2.25,8.92), (2.05,8.72,2.25,8.92), (2.05,8.72,2.25,8.92), (2.05,8.72,2.25,8.92), (2.48,8.72,2.68,8.92), (2.48,8.72,2.68,8.92), (2.48,8.72,2.68,8.92), (2.48,8.72,2.68,8.92), (2.48,8.72,2.68,8.92), (2.48,8.72,2.68,8.92), (5.49,8.72,5.69,8.92), (5.49,8.72,5.69,8.92), (5.49,8.72,5.69,8.92), (5.49,8.72,5.69,8.92), (5.49,8.72,5.69,8.92), (9.36,8.72,9.56,8.92), (9.36,8.72,9.56,8.92), (9.36,8.72,9.56,8.92), (9.36,8.72,9.56,8.92), (16.24,8.72,16.44,8.92), (16.24,8.72,16.44,8.92)])
A(comparator_0, met3, -0.4, -0.4, 4.24, 0.8, 3, 2, 3.44, 8.82)
R(comparator_0, met3, [(-0.165,-0.4,0.165,0.4), (5.855,-0.4,6.185,0.4), (5.855,-0.4,6.185,0.4), (5.855,-0.4,6.185,0.4), (5.855,-0.4,6.185,0.4), (5.855,-0.4,6.185,0.4), (8.865,-0.4,9.195,0.4), (8.865,-0.4,9.195,0.4), (8.865,-0.4,9.195,0.4), (8.865,-0.4,9.195,0.4), (9.92,-0.4,12.24,0.4), (11.44,-0.4,14.16,0.4), (12.735,-0.4,13.065,0.4), (12.735,-0.4,13.065,0.4), (12.735,-0.4,13.065,0.4), (13.36,-0.4,17.6,0.4), (17.035,-0.4,17.365,0.4), (17.035,-0.4,17.365,0.4), (13.155,5.9,13.485,6.7), (13.165,5.9,13.495,6.7), (13.175,5.9,13.475,6.7), (4.565,7.16,4.895,7.96), (4.565,7.16,4.895,7.96), (4.73,7.16,5.59,7.96), (5.425,7.16,5.755,7.96), (5.425,7.16,5.755,7.96), (1.985,8.42,2.315,9.22), (1.985,8.42,2.315,9.22), (1.985,8.42,2.315,9.22), (1.985,8.42,2.315,9.22), (1.985,8.42,2.315,9.22), (1.985,8.42,2.315,9.22), (1.985,8.42,2.315,9.22), (2.415,8.42,2.745,9.22), (2.415,8.42,2.745,9.22), (2.415,8.42,2.745,9.22), (2.415,8.42,2.745,9.22), (2.415,8.42,2.745,9.22), (2.415,8.42,2.745,9.22), (5.425,8.42,5.755,9.22), (5.425,8.42,5.755,9.22), (5.425,8.42,5.755,9.22), (5.425,8.42,5.755,9.22), (5.425,8.42,5.755,9.22), (9.295,8.42,9.625,9.22), (9.295,8.42,9.625,9.22), (9.295,8.42,9.625,9.22), (9.295,8.42,9.625,9.22), (9.92,8.42,12.24,9.22), (11.44,8.42,14.16,9.22), (11.675,8.42,12.005,9.22), (13.155,8.42,13.485,9.22), (13.155,8.42,13.485,9.22), (13.155,8.42,13.485,9.22), (13.36,8.42,17.6,9.22), (16.175,8.42,16.505,9.22), (16.175,8.42,16.505,9.22)])
R(comparator_0, via3, [(-0.1,-0.1,0.1,0.1), (13.22,6.2,13.42,6.4), (11.74,8.72,11.94,8.92), (13.22,8.72,13.42,8.92), (13.22,8.72,13.42,8.92), (13.22,8.72,13.42,8.92)])
R(comparator_0, met4, [(-0.59,-0.59,0.59,9.41), (11.25,-0.59,12.43,9.41), (-0.59,-0.165,0.59,0.165), (12.73,6.135,13.91,6.465), (12.73,6.3,13.91,8.82), (11.25,8.655,12.43,8.985), (12.73,8.655,13.91,8.985), (12.73,8.655,13.91,8.985), (12.73,8.655,13.91,8.985)])
R(comparator_0, L104_0, [(-4,-4,23.51,19.71)])
R(comparator_0, L235_5, [(0,0,19.51,15.71)])
comparator_0.add(gdstk.Reference(stage2_inv_90501218_pg0_, (15.48,0), rotation=pi, x_reflection=True))
comparator_0.add(gdstk.Reference(scm_pmos_23436893_x2_y1_, (3.44,7.56), x_reflection=True))
comparator_0.add(gdstk.Reference(inv_46031338_pg0_0_0_167, (15.48,0)))
comparator_0.add(gdstk.Reference(c_nmos_s_74334133_x2_y1_16_, (0,7.56), x_reflection=True))
comparator_0.add(gdstk.Reference(nmos_4t_77406006_x2_y1_1, (0.86,7.56)))
comparator_0.add(gdstk.Reference(nmos_4t_77406006_x2_y1_1, (4.3,7.56)))
comparator_0.add(gdstk.Label('OUT', (17.2,7.14), layer=68, texttype=5))
comparator_0.add(gdstk.Label('VBIAS', (1.72,2.94), layer=68, texttype=5))
comparator_0.add(gdstk.Label('VIN', (2.58,12.18), layer=68, texttype=5))
comparator_0.add(gdstk.Label('VREF', (6.02,12.18), layer=68, texttype=5))
comparator_0.add(gdstk.Label('VSS', (2.15,7.77), layer=69, texttype=5))
comparator_0.add(gdstk.Label('VSS', (11.84,4.41), layer=71, texttype=5))
comparator_0.add(gdstk.Label('VSS', (11.84,4.41), layer=71, texttype=5))
comparator_0.add(gdstk.Label('VSS', (11.84,4.41), layer=71, texttype=5))
comparator_0.add(gdstk.Label('VSS', (11.84,4.41), layer=71, texttype=5))
comparator_0.add(gdstk.Label('VSS', (11.84,4.41), layer=71, texttype=5))
comparator_0.add(gdstk.Label('VSS', (11.84,4.41), layer=71, texttype=5))
comparator_0.add(gdstk.Label('VSS', (11.84,4.41), layer=71, texttype=5))
comparator_0.add(gdstk.Label('VSS', (11.84,4.41), layer=71, texttype=5))
comparator_0.add(gdstk.Label('VSS', (11.84,4.41), layer=71, texttype=5))
comparator_0.add(gdstk.Label('VSS', (11.84,4.41), layer=71, texttype=5))
comparator_0.add(gdstk.Label('VSS', (11.84,4.41), layer=71, texttype=5))
comparator_0.add(gdstk.Label('VSS', (11.84,4.41), layer=71, texttype=5))
comparator_0.add(gdstk.Label('VSS', (11.84,4.41), layer=71, texttype=5))
comparator_0.add(gdstk.Label('VSS', (11.84,4.41), layer=71, texttype=5))
comparator_0.add(gdstk.Label('VSS', (11.84,4.41), layer=71, texttype=5))
comparator_0.add(gdstk.Label('VSS', (11.84,4.41), layer=71, texttype=5))
comparator_0.add(gdstk.Label('VSS', (11.84,4.41), layer=71, texttype=5))
comparator_0.add(gdstk.Label('VSS', (11.84,4.41), layer=71, texttype=5))
comparator_0.add(gdstk.Label('VSS', (11.84,4.41), layer=71, texttype=5))
comparator_0.add(gdstk.Label('VSS', (11.84,4.41), layer=71, texttype=5))
comparator_0.add(gdstk.Label('VDD', (6.45,0.63), layer=69, texttype=5))
comparator_0.add(gdstk.Label('VDD', (0,4.41), layer=71, texttype=5))
comparator_0.add(gdstk.Label('VDD', (0,4.41), layer=71, texttype=5))
comparator_0.add(gdstk.Label('VDD', (0,4.41), layer=71, texttype=5))
comparator_0.add(gdstk.Label('VDD', (0,4.41), layer=71, texttype=5))
comparator_0.add(gdstk.Label('VDD', (0,4.41), layer=71, texttype=5))
comparator_0.add(gdstk.Label('VDD', (0,4.41), layer=71, texttype=5))
comparator_0.add(gdstk.Label('VDD', (0,4.41), layer=71, texttype=5))
comparator_0.add(gdstk.Label('VDD', (0,4.41), layer=71, texttype=5))
comparator_0.add(gdstk.Label('VDD', (0,4.41), layer=71, texttype=5))
comparator_0.add(gdstk.Label('VDD', (0,4.41), layer=71, texttype=5))
comparator_0.add(gdstk.Label('VDD', (0,4.41), layer=71, texttype=5))
comparator_0.add(gdstk.Label('VDD', (0,4.41), layer=71, texttype=5))
comparator_0.add(gdstk.Label('VDD', (0,4.41), layer=71, texttype=5))
comparator_0.add(gdstk.Label('VDD', (0,4.41), layer=71, texttype=5))
comparator_0.add(gdstk.Label('VDD', (0,4.41), layer=71, texttype=5))
comparator_0.add(gdstk.Label('VDD', (0,4.41), layer=71, texttype=5))
comparator_0.add(gdstk.Label('VDD', (0,4.41), layer=71, texttype=5))
comparator_0.add(gdstk.Label('VDD', (0,4.41), layer=71, texttype=5))

lib.write_gds('COMPARATOR_0.gds')
